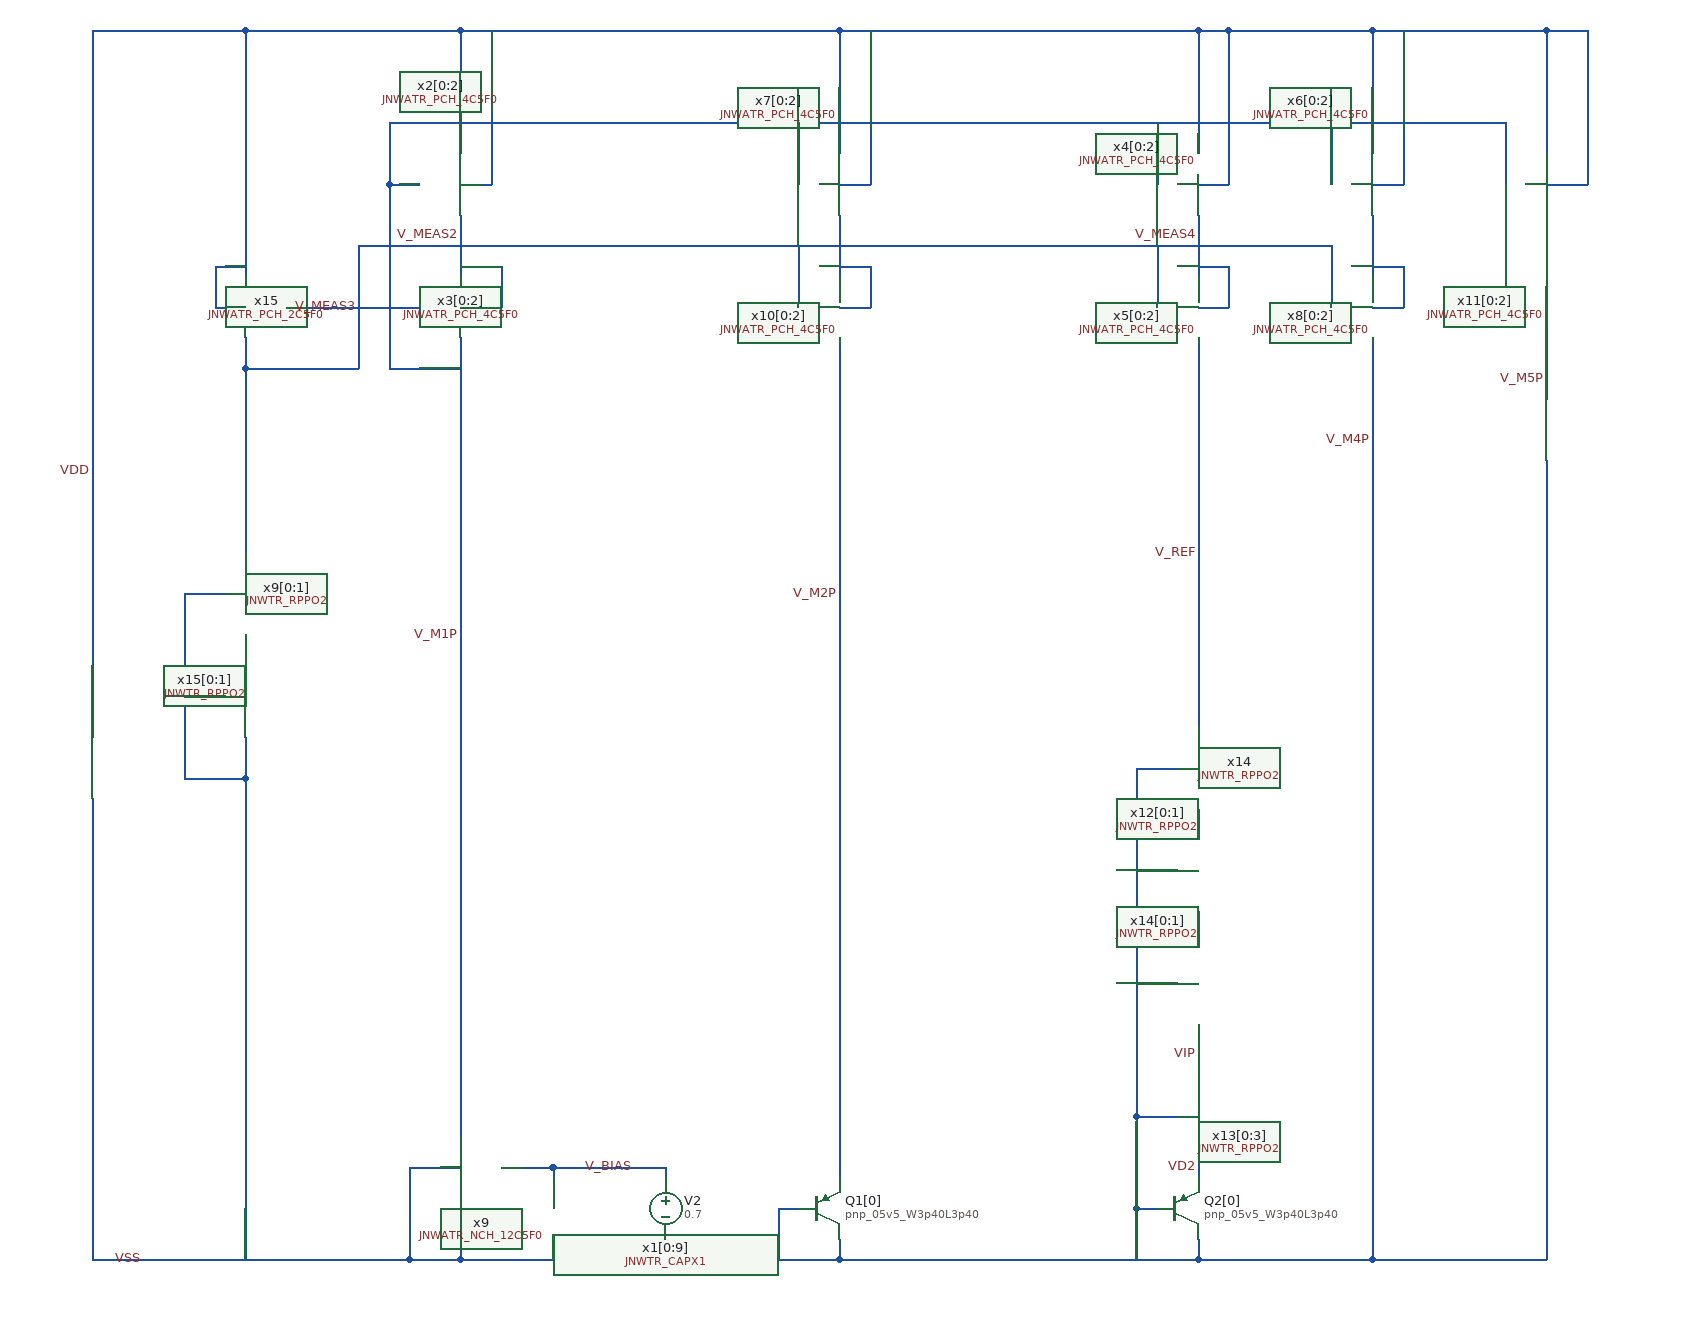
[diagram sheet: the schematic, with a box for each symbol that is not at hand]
v {xschem version=3.4.6 file_version=1.2}
G {}
K {}
V {}
S {}
E {}
N -940 0 -890 0 {lab=V_M4P}
N -890 -60 -890 0 {lab=V_M4P}
N -520 -100 -520 -80 {lab=V_M2P}
N -690 0 -520 0 {lab=V_M4P}
N -520 -20 -520 0 {lab=V_M4P}
N -580 -50 -560 -50 {lab=V_M4P}
N -580 -50 -580 0 {lab=V_M4P}
N -520 0 -350 0 {lab=V_M4P}
N -170 -20 -170 0 {lab=V_M4P}
N -230 -50 -210 -50 {lab=V_M4P}
N -230 -50 -230 0 {lab=V_M4P}
N -170 -100 -170 -80 {lab=VD2}
N -890 -500 -890 -260 {lab=V_M1P}
N -520 -480 -520 -240 {lab=V_M2P}
N -350 0 -170 0 {lab=V_M4P}
N -890 0 -690 0 {lab=V_M4P}
N -800 -90 -800 -80 {lab=V_BIAS}
N -850 -90 -800 -90 {lab=V_BIAS}
N -800 -10 -800 0 {lab=V_M4P}
N -170 -650 -170 -610 {lab=V_REF}
N -990 0 -940 0 {lab=V_M4P}
N -940 -90 -890 -90 {lab=V_M4P}
N -1120 -1200 -1100 -1200 {lab=VDD}
N -890 -1200 -890 -1080 {lab=VDD}
N -1100 -1200 -890 -1200 {lab=VDD}
N -890 -1200 -520 -1200 {lab=VDD}
N -520 -1200 -520 -1080 {lab=VDD}
N -520 -1200 -170 -1200 {lab=VDD}
N -170 -1200 -170 -1080 {lab=VDD}
N -890 -1020 -890 -960 {lab=V_MEAS2}
N -520 -1020 -520 -960 {lab=#net1}
N -170 -1020 -170 -960 {lab=V_MEAS4}
N 0 -1020 0 -960 {lab=#net2}
N -40 -1110 -40 -1050 {lab=V_M1P}
N -210 -1110 -210 -1050 {lab=V_M1P}
N -560 -1110 -560 -1050 {lab=V_M1P}
N -890 -900 -890 -810 {lab=V_M1P}
N -1100 -1200 -1100 -960 {lab=VDD}
N -1060 -930 -930 -930 {lab=V_MEAS3}
N -1100 -870 -990 -870 {lab=V_MEAS3}
N -990 -930 -990 -870 {lab=V_MEAS3}
N -960 -870 -890 -870 {lab=V_M1P}
N -960 -1050 -960 -870 {lab=V_M1P}
N -960 -1050 -930 -1050 {lab=V_M1P}
N -990 -990 -990 -930 {lab=V_MEAS3}
N -560 -990 -560 -930 {lab=V_MEAS3}
N -990 -990 -40 -990 {lab=V_MEAS3}
N -40 -990 -40 -930 {lab=V_MEAS3}
N -210 -990 -210 -930 {lab=V_MEAS3}
N -960 -1110 -960 -1050 {lab=V_M1P}
N -960 -1110 -40 -1110 {lab=V_M1P}
N -890 -1050 -860 -1050 {lab=VDD}
N -860 -1200 -860 -1050 {lab=VDD}
N -520 -1050 -490 -1050 {lab=VDD}
N -490 -1200 -490 -1050 {lab=VDD}
N -170 -1050 -140 -1050 {lab=VDD}
N -140 -1200 -140 -1050 {lab=VDD}
N 0 -1050 30 -1050 {lab=VDD}
N 0 -930 30 -930 {lab=#net2}
N 30 -970 30 -930 {lab=#net2}
N 0 -970 30 -970 {lab=#net2}
N -170 -930 -140 -930 {lab=V_MEAS4}
N -140 -970 -140 -930 {lab=V_MEAS4}
N -170 -970 -140 -970 {lab=V_MEAS4}
N -520 -930 -490 -930 {lab=#net1}
N -490 -970 -490 -930 {lab=#net1}
N -520 -970 -490 -970 {lab=#net1}
N -890 -930 -850 -930 {lab=V_MEAS2}
N -850 -970 -850 -930 {lab=V_MEAS2}
N -890 -970 -850 -970 {lab=V_MEAS2}
N -1130 -930 -1100 -930 {lab=VDD}
N -1130 -970 -1130 -930 {lab=VDD}
N -1130 -970 -1100 -970 {lab=VDD}
N -1200 0 -990 0 {lab=V_M4P}
N -1100 -870 -1100 -790 {lab=V_MEAS3}
N -1100 -900 -1100 -870 {lab=V_MEAS3}
N -520 -900 -520 -650 {lab=V_M2P}
N -1100 -430 -1100 -140 {lab=V_M4P}
N -520 -240 -520 -100 {lab=V_M2P}
N -170 -610 -170 -590 {lab=V_REF}
N -1100 -140 -1100 0 {lab=V_M4P}
N -890 -260 -890 -120 {lab=V_M1P}
N -170 -440 -170 -420 {lab=#net3}
N -170 -530 -170 -520 {lab=V_REF}
N -230 -140 -190 -140 {lab=V_M4P}
N -230 -140 -230 -50 {lab=V_M4P}
N -230 -480 -230 -140 {lab=V_M4P}
N -230 -480 -190 -480 {lab=V_M4P}
N -230 -380 -190 -380 {lab=V_M4P}
N -1100 -610 -1100 -590 {lab=#net4}
N -1100 -700 -1100 -690 {lab=V_MEAS3}
N -1160 -650 -1120 -650 {lab=V_M4P}
N -1160 -550 -1120 -550 {lab=V_M4P}
N -1100 -470 -1100 -430 {lab=V_M4P}
N -1160 -470 -1100 -470 {lab=V_M4P}
N -1100 -510 -1100 -470 {lab=V_M4P}
N -1160 -650 -1160 -470 {lab=V_M4P}
N -1100 -730 -1100 -700 {lab=V_MEAS3}
N -890 -810 -890 -670 {lab=V_M1P}
N -890 -670 -890 -610 {lab=V_M1P}
N -1100 -790 -1100 -730 {lab=V_MEAS3}
N -170 -590 -170 -530 {lab=V_REF}
N -170 0 0 0 {lab=V_M4P}
N -170 -1200 -140 -1200 {lab=VDD}
N 0 -870 0 -800 {lab=V_M4P}
N 0 -900 0 -870 {lab=V_M4P}
N 0 -1200 0 -1080 {lab=VDD}
N -140 -1200 0 -1200 {lab=VDD}
N 0 -1200 140 -1200 {lab=VDD}
N -940 -90 -940 0 {lab=V_M4P}
N 170 -1200 170 -1080 {lab=VDD}
N 170 -1050 210 -1050 {lab=VDD}
N 210 -1200 210 -1050 {lab=VDD}
N 170 -1200 210 -1200 {lab=VDD}
N 130 -1110 130 -1050 {lab=V_M1P}
N 170 -1020 170 -980 {lab=V_M5P}
N 140 -1200 170 -1200 {lab=VDD}
N -40 -1110 130 -1110 {lab=V_M1P}
N 30 -1200 30 -1050 {lab=VDD}
N -170 -340 -170 -320 {lab=#net5}
N -170 -190 -170 -180 {lab=VIP}
N -170 -320 -170 -310 {lab=#net5}
N -230 -270 -190 -270 {lab=V_M4P}
N -170 -230 -170 -190 {lab=VIP}
N -800 -90 -690 -90 {lab=V_BIAS}
N -520 -540 -520 -480 {lab=V_M2P}
N -170 -690 -170 -650 {lab=V_REF}
N -170 -900 -170 -800 {lab=V_REF}
N 0 -690 0 0 {lab=V_M4P}
N 170 -980 170 -860 {lab=V_M5P}
N 170 -750 170 0 {lab=V_M4P}
N 0 -0 170 0 {lab=V_M4P}
N -890 -610 -890 -580 {lab=V_M1P}
N -890 -520 -890 -500 {lab=V_M1P}
N -170 -710 -170 -690 {lab=V_REF}
N -170 -800 -170 -770 {lab=V_REF}
N 0 -800 -0 -770 {lab=V_M4P}
N 0 -710 -0 -690 {lab=V_M4P}
N 170 -780 170 -750 {lab=V_M4P}
N 170 -860 170 -840 {lab=V_M5P}
N -520 -570 -520 -540 {lab=V_M2P}
N -520 -650 -520 -630 {lab=V_M2P}
N -690 -90 -690 -80 {lab=V_BIAS}
N -690 -20 -690 -0 {lab=V_M4P}
N -1250 0 -1200 0 {lab=V_M4P}
N -1250 -450 -1250 0 {lab=V_M4P}
N -1250 -1200 -1250 -510 {lab=VDD}
N -1250 -1200 -1120 -1200 {lab=VDD}
N -890 -580 -890 -520 {lab=V_M1P}
N -520 -630 -520 -570 {lab=V_M2P}
N -170 -770 -170 -710 {lab=V_REF}
N 0 -770 0 -710 {lab=V_M4P}
C {sky130_fd_pr/pnp_05v5.sym} -540 -50 0 0 {name=Q1[0]
model=pnp_05v5_W3p40L3p40
m=1
spiceprefix=X
}
C {sky130_fd_pr/pnp_05v5.sym} -190 -50 0 0 {name=Q2[0]
model=pnp_05v5_W3p40L3p40
m=8
spiceprefix=X
}
C {JNW_TR_SKY130A/JNWTR_CAPX1.sym} -800 -20 0 0 {name=x1[0:9]}
C {devices/lab_wire.sym} -170 -200 0 0 {name=p6 sig_type=std_logic lab=VIP}
C {JNW_ATR_SKY130A/JNWATR_NCH_12C5F0.sym} -850 -90 0 1 {name=x9}
C {devices/lab_wire.sym} -170 -90 0 0 {name=p10 sig_type=std_logic lab=VD2
}
C {JNW_ATR_SKY130A/JNWATR_PCH_4C5F0.sym} -930 -930 0 0 {name=x3[0:2] }
C {JNW_ATR_SKY130A/JNWATR_PCH_4C5F0.sym} -210 -1050 0 0 {name=x4[0:2] }
C {JNW_ATR_SKY130A/JNWATR_PCH_4C5F0.sym} -210 -930 0 0 {name=x5[0:2] }
C {JNW_ATR_SKY130A/JNWATR_PCH_2C5F0.sym} -1060 -930 0 1 {name=x15}
C {JNW_ATR_SKY130A/JNWATR_PCH_4C5F0.sym} -40 -1050 0 0 {name=x6[0:2] }
C {JNW_ATR_SKY130A/JNWATR_PCH_4C5F0.sym} -40 -930 0 0 {name=x8[0:2] }
C {JNW_ATR_SKY130A/JNWATR_PCH_4C5F0.sym} -560 -1050 0 0 {name=x7[0:2] }
C {JNW_ATR_SKY130A/JNWATR_PCH_4C5F0.sym} -560 -930 0 0 {name=x10[0:2] }
C {devices/lab_wire.sym} -890 -610 0 0 {name=p1 sig_type=std_logic lab=V_M1P}
C {devices/lab_wire.sym} -890 -1000 0 0 {name=p12 sig_type=std_logic lab=V_MEAS2}
C {JNW_TR_SKY130A/JNWTR_RPPO2.sym} -170 -520 1 0 {name=x14}
C {JNW_TR_SKY130A/JNWTR_RPPO2.sym} -170 -420 1 0 {name=x12[0:1]}
C {JNW_TR_SKY130A/JNWTR_RPPO2.sym} -170 -180 1 0 {name=x13[0:3]}
C {JNW_TR_SKY130A/JNWTR_RPPO2.sym} -1100 -690 1 0 {name=x9[0:1]}
C {JNW_TR_SKY130A/JNWTR_RPPO2.sym} -1100 -590 1 0 {name=x15[0:1]}
C {devices/lab_wire.sym} -990 -930 0 0 {name=p13 sig_type=std_logic lab=V_MEAS3}
C {devices/lab_wire.sym} -170 -1000 0 0 {name=p14 sig_type=std_logic lab=V_MEAS4}
C {JNW_TR_SKY130A/JNWTR_RPPO2.sym} -170 -310 1 0 {name=x14[0:1]}
C {devices/lab_wire.sym} -520 -650 0 0 {name=p9 sig_type=std_logic lab=V_M2P}
C {devices/lab_wire.sym} -170 -690 0 0 {name=p17 sig_type=std_logic lab=V_REF}
C {devices/lab_wire.sym} 0 -800 0 0 {name=p18 sig_type=std_logic lab=V_M4P}
C {devices/lab_wire.sym} 170 -860 0 0 {name=p20 sig_type=std_logic lab=V_M5P}
C {devices/lab_wire.sym} -720 -90 0 0 {name=p3 sig_type=std_logic lab=V_BIAS}
C {JNW_ATR_SKY130A/JNWATR_PCH_4C5F0.sym} 130 -1050 0 0 {name=x11[0:2] }
C {JNW_ATR_SKY130A/JNWATR_PCH_4C5F0.sym} -930 -1050 0 0 {name=x2[0:2] }
C {devices/lab_wire.sym} -1200 0 0 0 {name=p2 sig_type=std_logic lab=VSS}
C {devices/lab_wire.sym} -1250 -770 0 0 {name=p4 sig_type=std_logic lab=VDD}
C {devices/vsource.sym} -690 -50 0 0 {name=V2 value=0.7 savecurrent=false}
